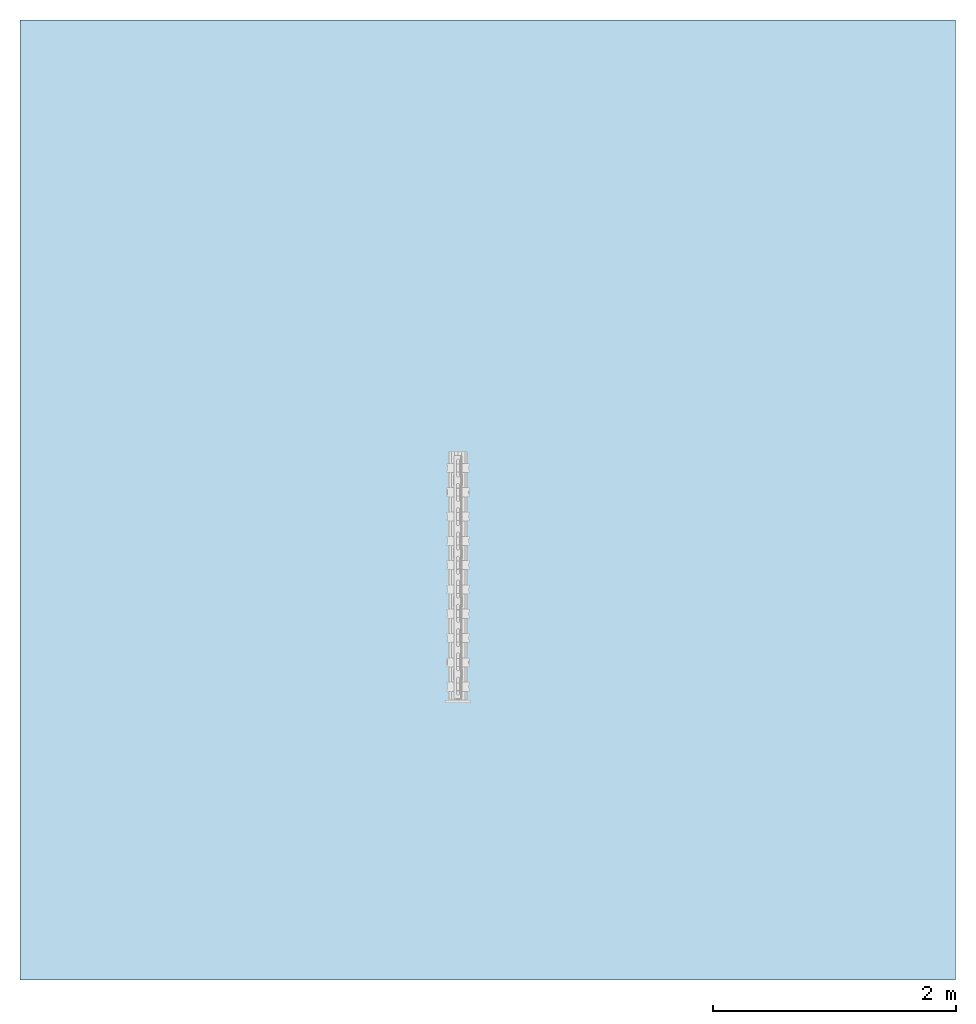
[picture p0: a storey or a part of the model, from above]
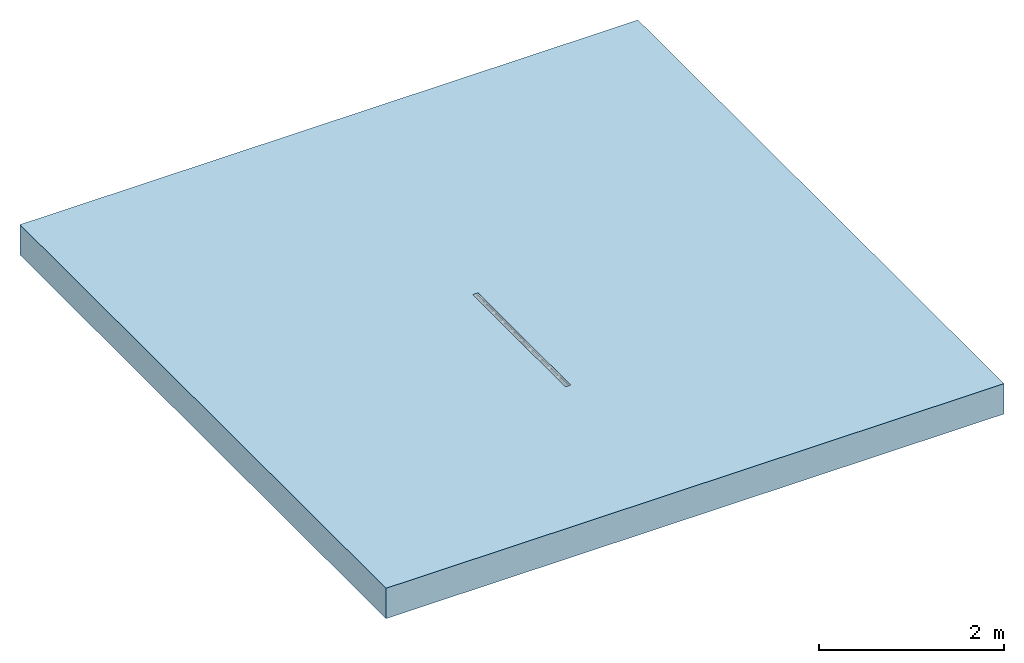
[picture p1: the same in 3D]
Properties of the parts of a building model (IFC2X3)

# File
Description: ViewDefinition [CoordinationView]
File name: 32990 - Q-Flow Edge - D.I.ifc
Time: 2013-08-14T09:24:23
Written by: Autodesk Revit 2013
Made in: 20120221_2030(x64)

# IfcProject, Project Number
LongName: Project Name; Phase: Project Status

# IfcSite, Default
RefLatitude: 42, 21, 30, 344238; RefLongitude: -71, -3, -35, -194702; RefElevation: 0 mm

# IfcBuilding
Pset_BuildingCommon - NumberOfStoreys: 1
Other - Client Name: Owner; Project Issue Date: Issue Date; Project Status: Project Status; Project Name: Project Name; Project Number: Project Number; Project Address: ## Street City, State Zip

# IfcBuildingStorey, Level 1
LongName: Level 1; Elevation: 0 mm
Constraints - Elevation Base: 0; Elevation: 0 mm
Graphics - Color: 0; Line Weight: 1; Line Pattern: Center; Symbol at End 2 Default: yes; Symbol at End 1 Default: no; Symbol: M_Level Head - Circle: M_Level Head - Circle
Identity Data - Name: Level 1; Building Story: yes; Structural: no
Dimensions - Computation Height: 0 mm

# IfcFlowTerminal: 32990 - Q-Flow Edge - D.I, Qmax 150:32990 - Q-Flow Edge - D.I:32990 - Q-Flow Edge - D.I:730922
In: Level 1
Construction - 32997_150 End Cap (at Male end): no; 32997_150 End Cap (at Female end): no; V_CoarseE1: yes; E3-QFlow-GalvSteel: no; E1-QFlow-DuctileIron: yes; V_Coarse_E5: no; E4-QGuard-GalvSteel: no; E2-QGuard-DuctileIron: no; E5-QSlot-GalvSteel: no
Identity Data - Mark: 77; Manufacturer: ACO Technologies plc - ACO Water Management Division; Maintenance Guidelines: http://www.aco.co.uk/download.php?id=220; Installation Guidelines: http://www.aco.co.uk/download.php?id=220; e-mail Sales: customersupport@aco.co.uk; e-mail Technical: technical@aco.co.uk; Telephone: +44 (0)1462 816666; Cost: 0; Assembly Code: D2040; Type Comments: ACO Qmax 150 channel assembly complete with ACO Q-Flow ductile iron edge rail; Product Code: 32990; Product Page URL: http://www.aco.co.uk/product_detail.php?id=79; Model: ACO Qmax 150; Address: ACO Business Park, Hitchin Road, Shefford, Bedfordshire, United Kingdom SG17 5TE; URL: www.aco.co.uk; Product Brochure: http://www.aco.co.uk/download.php?id=220; Model Description: High capacity slot drainage channel system; Price: POA - contact ACO; Assembly Description: Rain Water Drainage; OmniClass Title: Rainwater Removal; Fax: +44 (0)1462 815895; OmniClass Number: 23.70.50.24
Constraints - Moves With Nearby Elements: no; Level: Level: Level 1
Phasing - Phase Created: New Construction
Data - Concrete Surround Volume - Load Class F 900: 0.285 m³/m; Drainage Slot Width: 26mm; Concrete Surround Volume - Load Class E 600: 0.205 m³/m; Product Dimensions: 2000mm x 210mm x 400mm (LxWxH); Invert Depth: 350mm; Product Weight: 22kg; Installation - Reinforcement Details: Refer to brochure; Hydraulic Performance: http://www.aco.co.uk/download.php?id=220; Installation - Concrete Grade: Refer to brochure; Product Standard: BS EN 1433:2002 CE marked; Load Class: A 15 - F 900; ACO Hydraulic Design Software: http://www.acodesign.co.uk; Channel C.S.A: 17671mm²; Concrete Surround Volume - Load Class A 15 - D 400: 0.135 m³/m; Drainage Slot Intake Area: 18775mm²/m
Dimensions - BoreCentre: 277 mm; Length: 2000 mm; Floor Opening Width: 65 mm; Depth Overall: 400 mm; Width Overall: 210 mm; TopCoarse: 13 mm
General - TagNumber: 0; SerialNumber: 0
Green Building Properties - Channel Recycled Material Content: Variable %; Channel Recyclable: Fully recyclable; Seal Recyclable: Fully recyclable; Seal Recycled Material Content: 0%; Edge Rail Recycled Material Content: Between 40% - 90%; Edge Rail Recyclable: Fully recyclable
Model Properties - Multi-Functional End Cap - Seal Recyclable: Fully recyclable; Multi-Functional End Cap - Seal Recycled Material Content: 0%; Multi-Functional End Cap - Product Code: 32997; Multi-Functional End Cap - Channel Colour: Black; Multi-Functional End Cap - Channel Recycled Material Content: Variable %; Multi-Functional End Cap - Seal Material: Chloroprene; Multi-Functional End Cap - Weight: 1 kg; Multi-Functional End Cap - Channel Recyclable: Fully recyclable; Multi-Functional End Cap - Seal Colour: Black; Multi-Functional End Cap - Channel Material: Medium Density Polyethylene; Multi-Functional End Cap - Model Description: High capacity slot drainage channel system; Multi-Functional End Cap - Dimensions: Ø210mm x 240mm (ØxL)
Materials and Finishes - Edge Rail Finish: ATec coating; Edge Rail Colour: Black; Channel Colour: Black; Seal Material: Chloroprene; Edge Rail Material: Ductile Iron; Seal Colour: Black; Channel Material: Medium Density Polyethylene
Other - Revision: 1; Created by: www.aco.co.uk

# IfcOpeningElement: Opening
In: Level 1
Phasing - Phase Created: New Construction
Dimensions - Area: 60700000 mm2; Volume: 24168260000 mm3; Thickness: 400 mm; Perimeter: 31200 mm
Structural - Enable Analytical Model: no; Structural: no
Constraints - Level: Level: Level 1; Room Bounding: yes; Height Offset From Level: 0 mm; Related to Mass: no
Construction - Default Thickness: 400 mm; Function: 0
Graphics - Coarse Scale Fill Color: 0
Analytical Properties - Absorptance: 0.1; Roughness: 1
Materials and Finishes - Structural Material: Plant

# IfcSlab: Floor:Generic Floor - 400mm, Floor:Generic Floor - 400mm:193825
In: Level 1
PredefinedType: FLOOR; Material: Plant 400 mm
Phasing - Phase Created: New Construction
Dimensions - Area: 60700000 mm2; Volume: 24168260000 mm3; Thickness: 400 mm; Perimeter: 31200 mm
Structural - Enable Analytical Model: no; Structural: no
Constraints - Level: Level: Level 1; Room Bounding: yes; Height Offset From Level: 0 mm; Related to Mass: no
Pset_SlabCommon - Reference: Generic Floor - 400mm; IsExternal: no; LoadBearing: yes
Construction - Default Thickness: 400 mm; Function: 0
Graphics - Coarse Scale Fill Color: 0
Analytical Properties - Absorptance: 0.1; Roughness: 1
Materials and Finishes - Structural Material: Plant
